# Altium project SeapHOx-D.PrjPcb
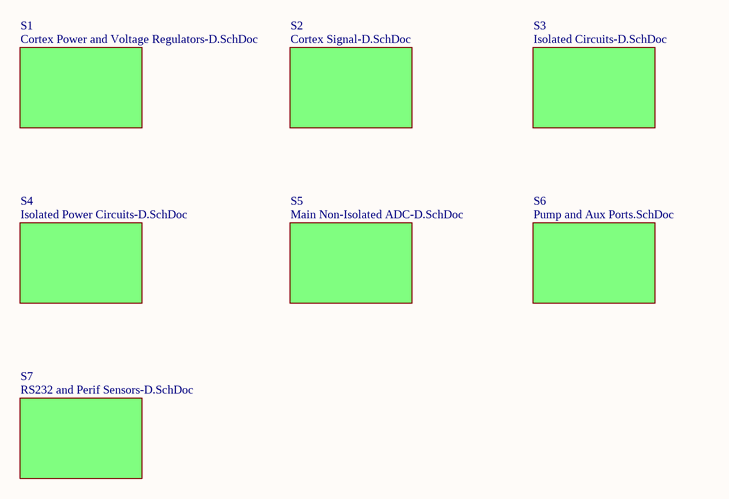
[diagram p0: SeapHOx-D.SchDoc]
1 sheet, 0 parts. Net scope: global (net labels, ports and power ports of the same name join across sheets).
Board file: SeapHOx-D.PcbDoc

## Sheet SeapHOx-D.SchDoc: SeapHOx ARM Controller
size Letter; PageSetup: Record=PageOptions¦CenterHorizontal=True¦CenterVertical=True¦PrintScale=0.94¦XCorrection=1.00¦YCorrection=1.00¦PrintKind=1¦BorderSize=5000000¦LeftOffset=0¦BottomOffset=0¦Orientation=2¦PaperLength=1000¦PaperWidth=1000¦Scale=100¦PaperSource=7¦PrintQuality=-4¦MediaType=1¦DitherType=10¦PaperKind=Letter¦PrintScaleMode=1

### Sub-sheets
S1 = Cortex Power and Voltage Regulators-D.SchDoc (file not in this document): no entries
S2 = Cortex Signal-D.SchDoc (file not in this document): no entries
S3 = Isolated Circuits-D.SchDoc (file not in this document): no entries
S4 = Isolated Power Circuits-D.SchDoc (file not in this document): no entries
S5 = Main Non-Isolated ADC-D.SchDoc (file not in this document): no entries
S6 = Pump and Aux Ports.SchDoc (file not in this document): no entries
S7 = RS232 and Perif Sensors-D.SchDoc (file not in this document): no entries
